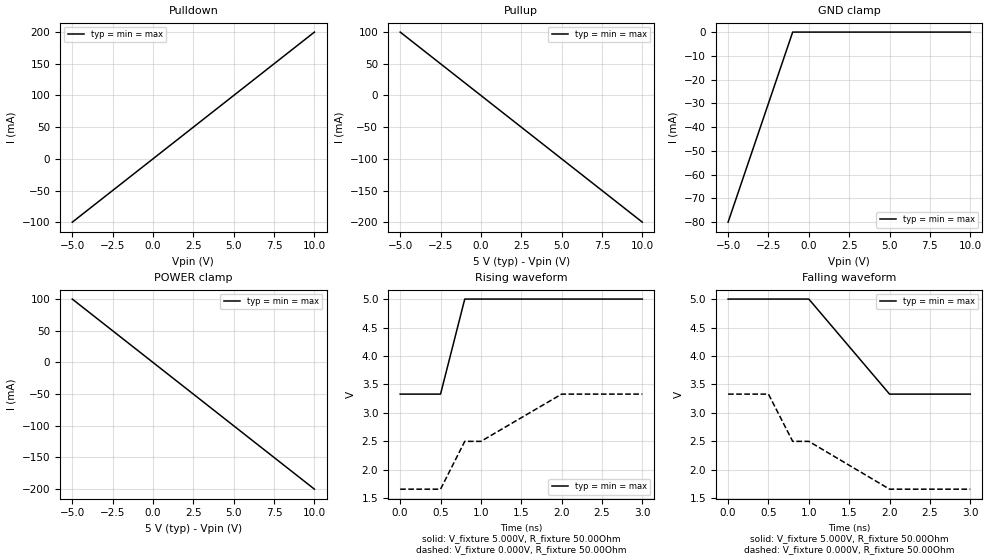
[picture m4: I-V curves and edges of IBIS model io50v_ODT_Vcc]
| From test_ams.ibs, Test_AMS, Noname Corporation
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[Model]   io50v_ODT_Vcc
Model_type   I/O
Vinl = 800.000mV
Vinh = 2.000V
Vmeas = 1.400V
Vref = 1.400V
Cref = 0.000F
Rref = 50.000Ohm
|   typ   min   max
C_comp   5.000pF   5.000pF   5.000pF
[Voltage Range]   5.000V   5.000V   5.000V
[Temperature Range]   50.0   100.0   0.0
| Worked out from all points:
|   slope of the pulldown table from 0 to 0.75 V, typ, clamps not added: 50 ohm
|   slope of the pullup table from 0 to 0.75 V, typ, clamps not added: 50 ohm
|   falling waveform, V_fixture 5.000V, R_fixture 50.00Ohm: 20-80 % time 600ps typ, 600ps min, 600ps max; typ from 5 V to 3.33 V
|   falling waveform, V_fixture 0.000V, R_fixture 50.00Ohm: 20-80 % time 982ps typ, 982ps min, 982ps max; typ from 3.33 V to 1.66 V
|   rising waveform, V_fixture 5.000V, R_fixture 50.00Ohm: 20-80 % time 180ps typ, 180ps min, 180ps max; typ from 3.33 V to 5 V
|   rising waveform, V_fixture 0.000V, R_fixture 50.00Ohm: 20-80 % time 978ps typ, 978ps min, 978ps max; typ from 1.66 V to 3.33 V
[Pulldown]
|   Voltage   I(typ)   I(min)   I(max)
-5V       -100mA     -100mA     -100mA
0V        0A         0A         0A
5V        100mA      100mA      100mA
10V       200mA      200mA      200mA
[GND Clamp]
|   Voltage   I(typ)   I(min)   I(max)
-5V       -80mA      -80mA      -80mA
-1V       0A         0A         0A
5V        0A         0A         0A
10V       0A         0A         0A
[Pullup]
|   Voltage   I(typ)   I(min)   I(max)
-5V       100mA      100mA      100mA
0V        0A         0A         0A
5V        -100mA     -100mA     -100mA
10V       -200mA     -200mA     -200mA
[POWER Clamp]
|   Voltage   I(typ)   I(min)   I(max)
-5V       100mA      100mA      100mA
0V        0A         0A         0A
5V        -100mA     -100mA     -100mA
10V       -200mA     -200mA     -200mA
[Ramp]
R_load = 50.00Ohm
|   typ   min   max
dV/dt_r   1.403V/1.248ns   1.116V/1.589ns   1.750V/927.496ps
dV/dt_f   1.513V/1.385ns   1.201V/1.726ns   1.878V/1.020ns
[Falling Waveform]
V_fixture = 5.000V
V_fixture_min = 5.000V
V_fixture_max = 5.000V
R_fixture = 50.00Ohm
|   Time   V(typ)   V(min)   V(max)
0s        5V         5V         5V
1ns       5V         5V         5V
2ns       3.33V      3.33V      3.33V
3ns       3.33V      3.33V      3.33V
[Falling Waveform]
V_fixture = 0.000V
V_fixture_min = 0.000V
V_fixture_max = 0.000V
R_fixture = 50.00Ohm
|   Time   V(typ)   V(min)   V(max)
0s        3.33V      3.33V      3.33V
500ps     3.33V      3.33V      3.33V
800ps     2.5V       2.5V       2.5V
1ns       2.5V       2.5V       2.5V
2ns       1.66V      1.66V      1.66V
3ns       1.66V      1.66V      1.66V
[Rising Waveform]
V_fixture = 5.000V
V_fixture_min = 5.000V
V_fixture_max = 5.000V
R_fixture = 50.00Ohm
|   Time   V(typ)   V(min)   V(max)
0s        3.33V      3.33V      3.33V
500ps     3.33V      3.33V      3.33V
800ps     5V         5V         5V
3ns       5V         5V         5V
[Rising Waveform]
V_fixture = 0.000V
V_fixture_min = 0.000V
V_fixture_max = 0.000V
R_fixture = 50.00Ohm
|   Time   V(typ)   V(min)   V(max)
0s        1.66V      1.66V      1.66V
500ps     1.66V      1.66V      1.66V
800ps     2.5V       2.5V       2.5V
1ns       2.5V       2.5V       2.5V
2ns       3.33V      3.33V      3.33V
3ns       3.33V      3.33V      3.33V
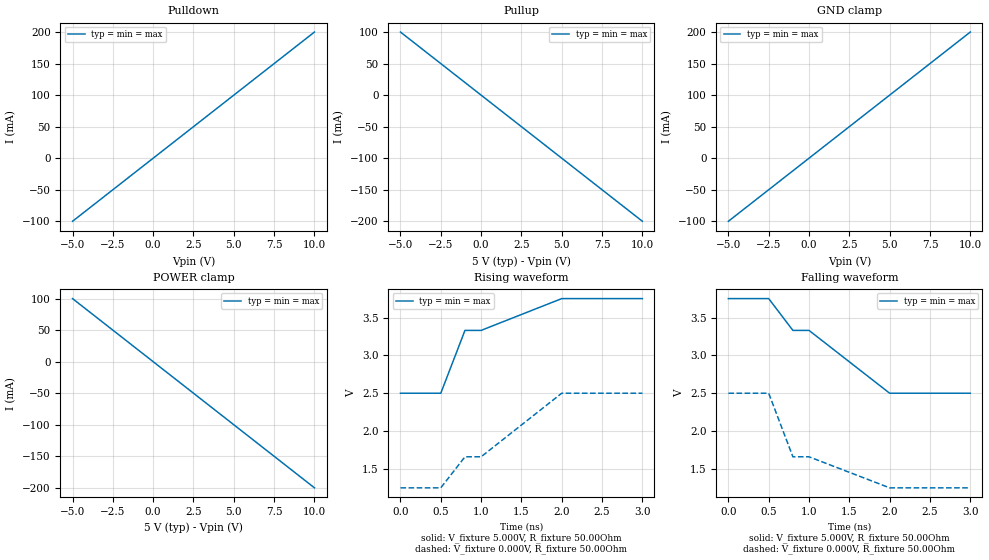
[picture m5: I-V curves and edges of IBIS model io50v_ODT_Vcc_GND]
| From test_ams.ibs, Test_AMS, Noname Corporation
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[Model]   io50v_ODT_Vcc_GND
Model_type   I/O
Vinl = 800.000mV
Vinh = 2.000V
Vmeas = 1.400V
Vref = 1.400V
Cref = 0.000F
Rref = 50.000Ohm
|   typ   min   max
C_comp   5.000pF   5.000pF   5.000pF
[Voltage Range]   5.000V   5.000V   5.000V
[Temperature Range]   50.0   100.0   0.0
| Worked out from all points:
|   slope of the pulldown table from 0 to 0.75 V, typ, clamps not added: 50 ohm
|   slope of the pullup table from 0 to 0.75 V, typ, clamps not added: 50 ohm
|   falling waveform, V_fixture 5.000V, R_fixture 50.00Ohm: 20-80 % time 1.02ns typ, 1.02ns min, 1.02ns max; typ from 3.75 V to 2.5 V
|   falling waveform, V_fixture 0.000V, R_fixture 50.00Ohm: 20-80 % time 801ps typ, 801ps min, 801ps max; typ from 2.5 V to 1.25 V
|   rising waveform, V_fixture 5.000V, R_fixture 50.00Ohm: 20-80 % time 814ps typ, 814ps min, 814ps max; typ from 2.5 V to 3.75 V
|   rising waveform, V_fixture 0.000V, R_fixture 50.00Ohm: 20-80 % time 1.02ns typ, 1.02ns min, 1.02ns max; typ from 1.25 V to 2.5 V
[Pulldown]
|   Voltage   I(typ)   I(min)   I(max)
-5V       -100mA     -100mA     -100mA
0V        0A         0A         0A
5V        100mA      100mA      100mA
10V       200mA      200mA      200mA
[GND Clamp]
|   Voltage   I(typ)   I(min)   I(max)
-5V       -100mA     -100mA     -100mA
0V        0A         0A         0A
5V        100mA      100mA      100mA
10V       200mA      200mA      200mA
[Pullup]
|   Voltage   I(typ)   I(min)   I(max)
-5V       100mA      100mA      100mA
0V        0A         0A         0A
5V        -100mA     -100mA     -100mA
10V       -200mA     -200mA     -200mA
[POWER Clamp]
|   Voltage   I(typ)   I(min)   I(max)
-5V       100mA      100mA      100mA
0V        0A         0A         0A
5V        -100mA     -100mA     -100mA
10V       -200mA     -200mA     -200mA
[Ramp]
R_load = 50.00Ohm
|   typ   min   max
dV/dt_r   1.403V/1.248ns   1.116V/1.589ns   1.750V/927.496ps
dV/dt_f   1.513V/1.385ns   1.201V/1.726ns   1.878V/1.020ns
[Falling Waveform]
V_fixture = 5.000V
V_fixture_min = 5.000V
V_fixture_max = 5.000V
R_fixture = 50.00Ohm
|   Time   V(typ)   V(min)   V(max)
0s        3.75V      3.75V      3.75V
500ps     3.75V      3.75V      3.75V
800ps     3.33V      3.33V      3.33V
1ns       3.33V      3.33V      3.33V
2ns       2.5V       2.5V       2.5V
3ns       2.5V       2.5V       2.5V
[Falling Waveform]
V_fixture = 0.000V
V_fixture_min = 0.000V
V_fixture_max = 0.000V
R_fixture = 50.00Ohm
|   Time   V(typ)   V(min)   V(max)
0s        2.5V       2.5V       2.5V
500ps     2.5V       2.5V       2.5V
800ps     1.66V      1.66V      1.66V
1ns       1.66V      1.66V      1.66V
2ns       1.25V      1.25V      1.25V
3ns       1.25V      1.25V      1.25V
[Rising Waveform]
V_fixture = 5.000V
V_fixture_min = 5.000V
V_fixture_max = 5.000V
R_fixture = 50.00Ohm
|   Time   V(typ)   V(min)   V(max)
0s        2.5V       2.5V       2.5V
500ps     2.5V       2.5V       2.5V
800ps     3.33V      3.33V      3.33V
1ns       3.33V      3.33V      3.33V
2ns       3.75V      3.75V      3.75V
3ns       3.75V      3.75V      3.75V
[Rising Waveform]
V_fixture = 0.000V
V_fixture_min = 0.000V
V_fixture_max = 0.000V
R_fixture = 50.00Ohm
|   Time   V(typ)   V(min)   V(max)
0s        1.25V      1.25V      1.25V
500ps     1.25V      1.25V      1.25V
800ps     1.66V      1.66V      1.66V
1ns       1.66V      1.66V      1.66V
2ns       2.5V       2.5V       2.5V
3ns       2.5V       2.5V       2.5V
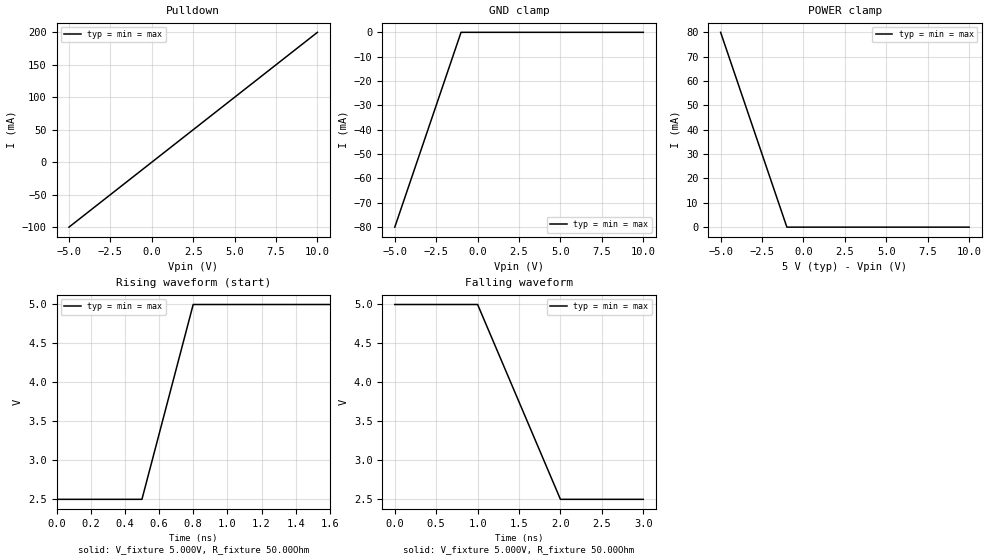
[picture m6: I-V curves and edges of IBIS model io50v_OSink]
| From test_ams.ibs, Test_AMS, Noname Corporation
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[Model]   io50v_OSink
Model_type   I/O_open_sink
Vinl = 800.000mV
Vinh = 2.000V
Vmeas = 1.400V
Vref = 1.400V
Cref = 0.000F
Rref = 50.000Ohm
|   typ   min   max
C_comp   5.000pF   5.000pF   5.000pF
[Voltage Range]   5.000V   5.000V   5.000V
[Temperature Range]   50.0   100.0   0.0
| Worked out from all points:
|   slope of the pulldown table from 0 to 0.75 V, typ, clamps not added: 50 ohm
|   falling waveform, V_fixture 5.000V, R_fixture 50.00Ohm: 20-80 % time 600ps typ, 600ps min, 600ps max; typ from 5 V to 2.5 V
|   rising waveform, V_fixture 5.000V, R_fixture 50.00Ohm: 20-80 % time 180ps typ, 180ps min, 180ps max; typ from 2.5 V to 5 V
[Pulldown]
|   Voltage   I(typ)   I(min)   I(max)
-5V       -100mA     -100mA     -100mA
0V        0A         0A         0A
5V        100mA      100mA      100mA
10V       200mA      200mA      200mA
[GND Clamp]
|   Voltage   I(typ)   I(min)   I(max)
-5V       -80mA      -80mA      -80mA
-1V       0A         0A         0A
5V        0A         0A         0A
10V       0A         0A         0A
[POWER Clamp]
|   Voltage   I(typ)   I(min)   I(max)
-5V       80mA       80mA       80mA
-1V       0A         0A         0A
5V        0A         0A         0A
10V       0A         0A         0A
[Ramp]
R_load = 50.00Ohm
|   typ   min   max
dV/dt_r   1.403V/1.248ns   1.116V/1.589ns   1.750V/927.496ps
dV/dt_f   1.513V/1.385ns   1.201V/1.726ns   1.878V/1.020ns
[Falling Waveform]
V_fixture = 5.000V
V_fixture_min = 5.000V
V_fixture_max = 5.000V
R_fixture = 50.00Ohm
|   Time   V(typ)   V(min)   V(max)
0s        5V         5V         5V
1ns       5V         5V         5V
2ns       2.5V       2.5V       2.5V
3ns       2.5V       2.5V       2.5V
[Rising Waveform]
V_fixture = 5.000V
V_fixture_min = 5.000V
V_fixture_max = 5.000V
R_fixture = 50.00Ohm
|   Time   V(typ)   V(min)   V(max)
0s        2.5V       2.5V       2.5V
500ps     2.5V       2.5V       2.5V
800ps     5V         5V         5V
3ns       5V         5V         5V
